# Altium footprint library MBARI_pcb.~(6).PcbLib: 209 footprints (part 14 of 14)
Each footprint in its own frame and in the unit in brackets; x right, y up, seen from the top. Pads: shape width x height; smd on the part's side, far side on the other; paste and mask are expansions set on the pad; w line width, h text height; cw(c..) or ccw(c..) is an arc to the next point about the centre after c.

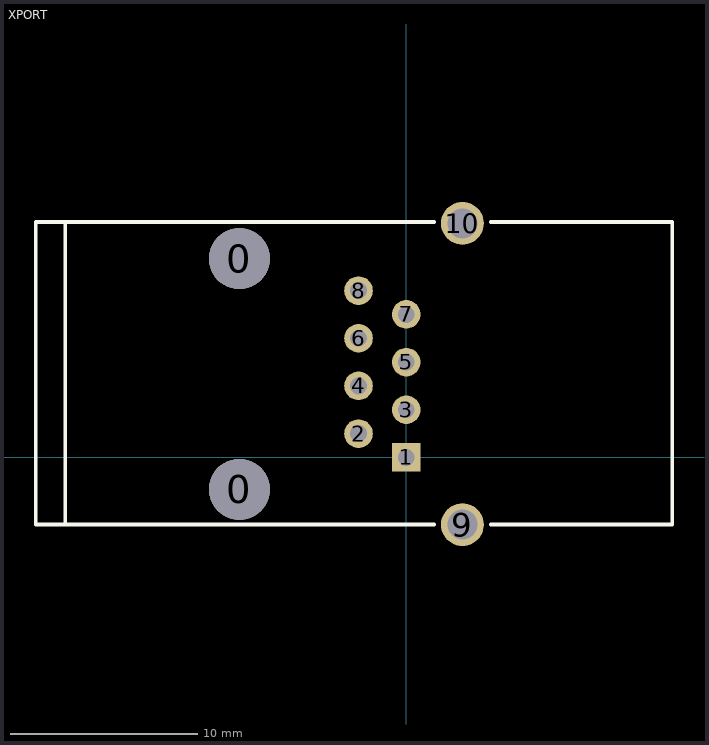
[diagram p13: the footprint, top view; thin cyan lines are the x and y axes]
## XPORT [mil]
pads (12):
  round 128 hole 128 unplated: 0(-350,-67) 0(-350,417)
  rect 60x60 hole 35: 1(0,0)
  round 60 hole 35: 2(-100,50) 3(0,100) 4(-100,150) 5(0,200) 6(-100,250) 7(0,300) 8(-100,350)
  round 90 hole 63: 9(118,-141) 10(118,491)
TopOverlay:
  lines w7: -715,-141 -715,494
  lines w8: 58,-141 -777,-141 -777,-121 -777,494 58,494 ; 178,-141 558,-141 558,494 178,494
